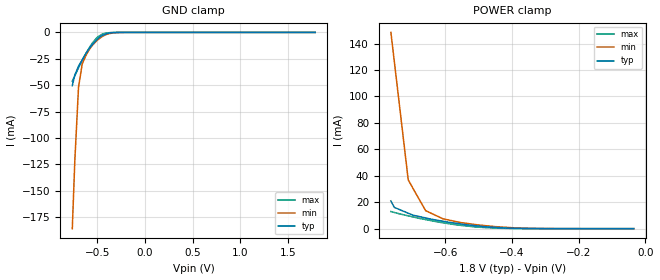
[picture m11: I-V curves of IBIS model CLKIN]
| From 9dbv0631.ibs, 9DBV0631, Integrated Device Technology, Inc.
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|   Model CLKIN
[Model]   CLKIN
Model_type   Input
Polarity   Non-Inverting
Vinl = 0.63V
Vinh = 1.17V
|   typ   min   max
C_comp   2pF   1.5pF   2.5pF
|   typ   min   max
[Voltage range]   1.8V   1.7V   1.9V
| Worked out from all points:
|   GND clamp passes 1 mA (typ) near -0.39 V on its own axis
|   POWER clamp passes 1 mA (typ) near -0.45 V on its own axis
[GND_clamp]
|Voltage   I (typ)   I (min)   I (max)
|Note, modeling breaks down at 250mA and above.  This is well beyond the functional   |
|operating range of the device.  Should this scenario occur, catastrophic failure and   |
|possible damage to the device and/or board is of higher concern than the I-V curve   |
|behavior.  The IBIS checker will flag currents in excess of 10A with warnings.  Lines   |
|with currents in excess of 0.35 A have been commented out.  The points still remain|
|available to the user if the user desires to use them.   |
|-1.84184e+00   -4.43726e+01   -3.75529e+01   -5.11219e+01
|-1.78367e+00   -4.35813e+01   -3.75529e+01   -4.77297e+01
|-1.72551e+00   -4.07622e+01   -3.75529e+01   -4.43374e+01
|-1.68980e+00   -3.90312e+01   -3.71251e+01   -4.22543e+01
|-1.64796e+00   -3.70034e+01   -3.53709e+01   -3.98142e+01
|-1.60918e+00   -3.51239e+01   -3.37451e+01   -3.75526e+01
|-1.57959e+00   -3.36896e+01   -3.25043e+01   -3.58266e+01
|-1.54388e+00   -3.19585e+01   -3.10067e+01   -3.37435e+01
|-1.49286e+00   -2.94854e+01   -2.88674e+01   -3.07676e+01
|-1.46939e+00   -2.83478e+01   -2.78832e+01   -2.93987e+01
|-1.43469e+00   -2.66661e+01   -2.64285e+01   -2.73750e+01
|-1.38776e+00   -2.43909e+01   -2.44602e+01   -2.46371e+01
|-1.35918e+00   -2.30059e+01   -2.32621e+01   -2.29706e+01
|-1.31837e+00   -2.10274e+01   -2.15505e+01   -2.05898e+01
|-1.28367e+00   -1.93456e+01   -2.00957e+01   -1.85661e+01
|-1.24898e+00   -1.76639e+01   -1.86409e+01   -1.65424e+01
|-1.20204e+00   -1.53885e+01   -1.66725e+01   -1.38044e+01
|-1.17959e+00   -1.43003e+01   -1.57312e+01   -1.24949e+01
|-1.13878e+00   -1.23218e+01   -1.40196e+01   -1.01140e+01
|-1.08571e+00   -9.74968e+00   -1.17946e+01   -7.01883e+00
|-1.07551e+00   -9.25505e+00   -1.13667e+01   -6.42361e+00
|-1.02755e+00   -6.93027e+00   -9.35566e+00   -3.62605e+00
|-9.73469e-01   -4.30875e+00   -7.08793e+00   -8.78143e-01
|-9.69388e-01   -4.11092e+00   -6.91679e+00   -6.70754e-01
|-9.18367e-01   -1.63803e+00   -4.77749e+00   -1.81535e-01
|-8.67347e-01   -3.93222e-01   -2.63828e+00   -7.78700e-02
|-8.53061e-01   -2.53802e-01   -2.12593e+00   -6.64177e-02
|-8.08163e-01   -7.85268e-02   -6.91421e-01   -5.57542e-02
-763.3mV  -50.4mA    -185.9mA   -46.26mA
-736.7mV  -40.46mA   -121.4mA   -40.95mA
-698mV    -32.04mA   -51.96mA   -33.61mA
-659.2mV  -25.86mA   -29.9mA    -26.57mA
-620.4mV  -20.15mA   -21.89mA   -19.82mA
-587.8mV  -15.62mA   -16.69mA   -14.97mA
-555.1mV  -11.83mA   -12.54mA   -10.4mA
-504.1mV  -6.773mA   -7.631mA   -4.854mA
-445.9mV  -2.89mA    -3.687mA   -1.475mA
-399mV    -1.185mA   -1.676mA   -541uA
-294.9mV  -85.59uA   -180.4uA   -23.42uA
1.787V    3.903nA    237nA      117.1pA
[Power_clamp]
|Voltage   I (typ)   I (min)   I (max)
|Note, modeling breaks down at 250mA and above.  This is well beyond the functional   |
|operating range of the device.  Should this scenario occur, catastrophic failure and   |
|possible damage to the device and/or board is of higher concern than the I-V curve   |
|behavior.  The IBIS checker will flag currents in excess of 10A with warnings.  Lines   |
|with currents in excess of 0.35 A have been commented out.  The points still remain|
|available to the user if the user desires to use them.   |
|-1.90000e+00   5.60662e+01   4.77602e+01   6.81385e+01
|-1.84184e+00   5.60662e+01   4.77602e+01   6.38558e+01
|-1.80000e+00   5.60662e+01   4.77602e+01   6.07752e+01
|-1.78367e+00   5.50536e+01   4.77602e+01   5.95731e+01
|-1.74490e+00   5.26485e+01   4.77602e+01   5.67179e+01
|-1.72551e+00   5.14459e+01   4.77602e+01   5.52904e+01
|-1.70000e+00   4.98637e+01   4.77602e+01   5.34120e+01
|-1.68980e+00   4.92308e+01   4.72076e+01   5.26606e+01
|-1.66735e+00   4.78384e+01   4.59921e+01   5.10076e+01
|-1.64796e+00   4.66358e+01   4.49423e+01   4.95801e+01
|-1.63469e+00   4.58130e+01   4.42240e+01   4.86033e+01
|-1.60918e+00   4.42308e+01   4.28427e+01   4.67250e+01
|-1.59592e+00   4.34080e+01   4.21244e+01   4.57482e+01
|-1.57959e+00   4.23954e+01   4.12404e+01   4.45461e+01
|-1.55102e+00   4.06232e+01   3.96933e+01   4.24423e+01
|-1.54388e+00   4.01802e+01   3.93066e+01   4.19163e+01
|-1.52449e+00   3.89777e+01   3.82568e+01   4.04888e+01
|-1.49286e+00   3.70157e+01   3.65440e+01   3.81596e+01
|-1.49184e+00   3.69524e+01   3.64888e+01   3.80845e+01
|-1.46939e+00   3.55600e+01   3.52732e+01   3.64316e+01
|-1.43980e+00   3.37247e+01   3.36710e+01   3.42527e+01
|-1.43469e+00   3.34082e+01   3.33947e+01   3.38770e+01
|-1.41429e+00   3.21424e+01   3.22897e+01   3.23743e+01
|-1.38776e+00   3.04969e+01   3.08532e+01   3.04209e+01
|-1.37653e+00   2.98008e+01   3.02455e+01   2.95944e+01
|-1.35918e+00   2.87249e+01   2.93062e+01   2.83172e+01
|-1.33571e+00   2.72692e+01   2.80355e+01   2.65891e+01
|-1.31837e+00   2.61933e+01   2.70962e+01   2.53119e+01
|-1.30408e+00   2.53073e+01   2.63228e+01   2.42600e+01
|-1.28367e+00   2.40416e+01   2.52178e+01   2.27574e+01
|-1.26020e+00   2.25860e+01   2.39471e+01   2.10293e+01
|-1.24898e+00   2.18898e+01   2.33393e+01   2.02029e+01
|-1.23163e+00   2.08139e+01   2.24001e+01   1.89257e+01
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-763.3mV  20.98mA    148.5mA    12.93mA
-753.1mV  16.09mA    126.6mA    12.25mA
-711.2mV  11.67mA    36.84mA    9.69mA
-698mV    10.27mA    30.93mA    8.925mA
-659.2mV  8.1mA      13.64mA    6.86mA
-607.1mV  5.621mA    7.447mA    4.453mA
-555.1mV  3.622mA    4.685mA    2.527mA
-451mV    999.8uA    1.546mA    418.9uA
-346.9mV  115.6uA    255.6uA    28.77uA
-34.69mV  5.354nA    84.02nA    174.7pA
